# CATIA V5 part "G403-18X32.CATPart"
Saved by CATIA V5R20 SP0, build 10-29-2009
Part number: G403-18X32
Definition: NONE
Nomenclature: G403-18X32
Source: Unknown
Description: G403-18X32
Bounding box of the stored display mesh (mm): x -16 to 16, y -15 to 15, z -15 to 15
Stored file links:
  C:\Users\Utente\Desktop\IO LAVORO\3D X SITO CF\X SITO\PLASTICA\G403\G403-18X32.CATPart

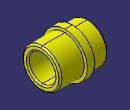
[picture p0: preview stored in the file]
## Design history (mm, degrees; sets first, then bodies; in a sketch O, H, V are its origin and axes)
Body1 "G403-18X32" (main body)
  Solid1: solid without history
